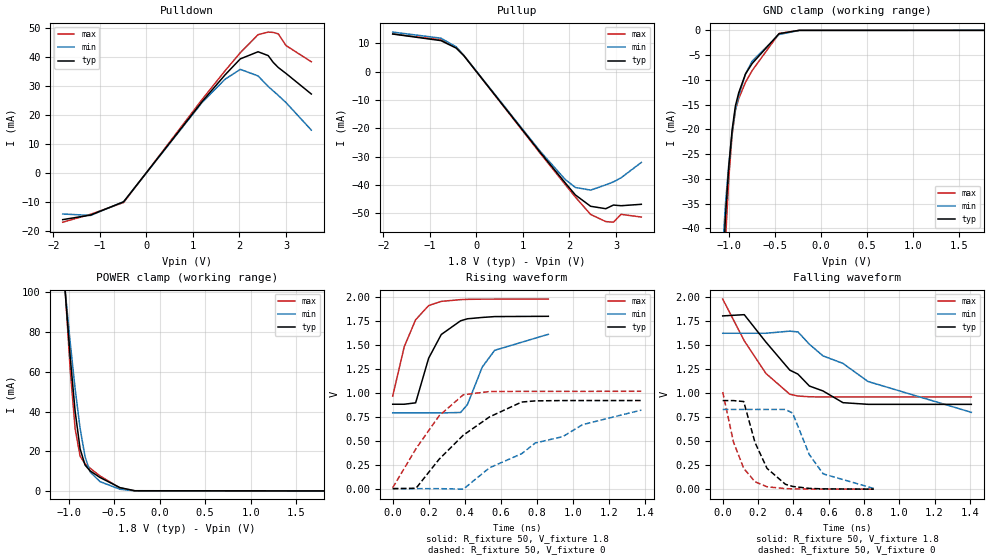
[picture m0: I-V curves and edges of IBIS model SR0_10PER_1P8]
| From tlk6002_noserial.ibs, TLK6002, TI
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[Model]   SR0_10PER_1P8
Model_type   3-state
Polarity   Non-Inverting
Enable   Active-Low
Cref =  15.0000pF
Rref =  100.0000M
Vref =  0V
Vmeas =  0.9
C_comp   1.885425p   1.715283p   2.176444p
[Temperature Range]   25   125   -40
[Voltage Range]   1.8   1.62   1.98
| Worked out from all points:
|   slope of the pulldown table from 0 to 0.27 V, typ, clamps not added: 47.1 ohm
|   slope of the pullup table from 0 to 0.27 V, typ, clamps not added: 47.4 ohm
|   GND clamp passes 1 mA (typ) near -0.48 V on its own axis
|   POWER clamp passes 1 mA (typ) near -0.39 V on its own axis
|   rising waveform, R_fixture 50, V_fixture 1.8: 20-80 % time 116ps typ, 136ps min, 105ps max; typ from 0.881 V to 1.8 V
|   rising waveform, R_fixture 50, V_fixture 0: 20-80 % time 335ps typ, 539ps min, 235ps max; typ from 0 V to 0.92 V
|   falling waveform, R_fixture 50, V_fixture 1.8: 20-80 % time 303ps typ, 537ps min, 219ps max; typ from 1.8 V to 0.882 V
|   falling waveform, R_fixture 50, V_fixture 0: 20-80 % time 117ps typ, 135ps min, 99.2ps max; typ from 0.921 V to 0.001 V
[POWER_clamp]
-1.8V     644.6mA    525mA      777mA
-1.055V   111.8mA    110.1mA    115.1mA
-1.036V   100.1mA    100.9mA    100.7mA
-981.8mV  67.73mA    75.06mA    61.46mA
-927.3mV  40.06mA    51.42mA    31.32mA
-872.7mV  21.16mA    31.46mA    17.47mA
-818.2mV  13.02mA    17.22mA    13.65mA
-763.6mV  10.12mA    9.635mA    11.46mA
-654.5mV  6.765mA    4.687mA    7.551mA
-436.4mV  1.678mA    857.7uA    1.497mA
-272.7mV  101.6uA    39.42uA    61.35uA
1.8V      90.02nA    111.7nA    348.8nA
[Pulldown]
-1.8V     -16mA      -14.06mA   -16.88mA
-1.2V     -14.43mA   -14.55mA   -14.16mA
-490.9mV  -9.876mA   -9.852mA   -10.12mA
1.2V      24.63mA    24.33mA    25.37mA
1.691V    33.76mA    32.26mA    35.17mA
2.018V    39.25mA    35.65mA    41.38mA
2.4V      41.7mA     33.4mA     47.57mA
2.618V    40.38mA    29.76mA    48.46mA
2.727V    38.02mA    28.23mA    48.35mA
2.836V    36.27mA    26.68mA    47.83mA
3V        34.26mA    24.25mA    43.84mA
3.545V    27.17mA    14.78mA    38.26mA
[Pullup]
-1.8V     13.31mA    13.99mA    13.35mA
-763.6mV  10.98mA    11.84mA    11.28mA
-436.4mV  8.351mA    8.806mA    8.623mA
-272.7mV  5.714mA    5.817mA    5.773mA
1.364V    -28.29mA   -27.93mA   -28.62mA
1.909V    -39.21mA   -38.01mA   -39.8mA
2.127V    -43.46mA   -40.83mA   -44.21mA
2.455V    -47.47mA   -41.76mA   -50.35mA
2.782V    -48.32mA   -39.91mA   -52.87mA
2.945V    -47.03mA   -38.87mA   -53.08mA
3.109V    -47.27mA   -37.41mA   -50.31mA
3.545V    -46.77mA   -32.01mA   -51.27mA
[GND_clamp]
-1.8V     -566.4mA   -409.5mA   -760.6mA
-1.073V   -54mA      -46.59mA   -65.57mA
-1.036V   -37.78mA   -35.21mA   -42.82mA
-1V       -27.67mA   -27.21mA   -30.08mA
-963.6mV  -20.15mA   -20.81mA   -21.18mA
-927.3mV  -15.22mA   -16.02mA   -16.11mA
-890.9mV  -12.56mA   -13.16mA   -13.75mA
-818.2mV  -8.811mA   -8.807mA   -10.5mA
-745.5mV  -6.683mA   -6.208mA   -8.112mA
-454.5mV  -667.9uA   -843.5uA   -644.9uA
-236.4mV  -5uA       -16.82uA   -2.48uA
1.764V    74.33nA    1.736uA    140.7nA
[Ramp]
dV/dt_f  0.4683422/0.2556061n  0.4296108/0.4864909n  0.5160574/0.1742076n
dV/dt_r  0.4626691/0.2841825n  0.4174943/0.4785458n  0.5102716/0.1846147n
R_load = 50
[Rising Waveform]
R_fixture = 50
V_fixture = 1.8
V_fixture_min = 1.62
V_fixture_max = 1.98
0s        881.4mV    790.8mV    966.8mV
64ps      881.5mV    790.8mV    1.483V
127ps     896.1mV    790.8mV    1.764V
199ps     1.362V     790.8mV    1.912V
269ps     1.61V      790.8mV    1.956V
376ps     1.753V     795.4mV    1.974V
414ps     1.774V     878.7mV    1.977V
496ps     1.788V     1.27V      1.979V
565ps     1.797V     1.445V     1.979V
862ps     1.8V       1.612V     1.98V
[Rising Waveform]
R_fixture = 50
V_fixture = 0
V_fixture_min = 0
V_fixture_max = 0
0s        2.289uV    1.08uV     9.049mV
129ps     3.596mV    971.8nV    417.7mV
257ps     306.8mV    -29.71uV   760.6mV
391ps     558.4mV    -5.602mV   980.4mV
536ps     749mV      217.7mV    1.014V
714ps     904.2mV    364.6mV    1.016V
790ps     916.6mV    477.1mV    1.016V
942ps     919.8mV    543.1mV    1.016V
1.051ns   919.9mV    667.8mV    1.016V
1.377ns   920.2mV    820.6mV    1.017V
[Falling Waveform]
R_fixture = 50
V_fixture = 1.8
V_fixture_min = 1.62
V_fixture_max = 1.98
0s        1.8V       1.62V      1.975V
122ps     1.813V     1.62V      1.542V
244ps     1.53V      1.62V      1.204V
380ps     1.237V     1.642V     986.7mV
426ps     1.196V     1.634V     968.4mV
491ps     1.072V     1.506V     960.4mV
568ps     1.021V     1.385V     958.9mV
681ps     899.3mV    1.307V     958.8mV
823ps     882.1mV    1.119V     958.7mV
1.408ns   881.7mV    799.1mV    958.5mV
[Falling Waveform]
R_fixture = 50
V_fixture = 0
V_fixture_min = 0
V_fixture_max = 0
0s        920.9mV    828.9mV    1.009V
61ps      920.8mV    828.9mV    490.5mV
119ps     911mV      828.9mV    217.3mV
183ps     484.9mV    828.9mV    78.07mV
251ps     217.2mV    829mV      26.07mV
355ps     52.24mV    828.9mV    6.935mV
396ps     29.63mV    791.1mV    4.463mV
490ps     9.417mV    361.9mV    2.735mV
569ps     4.315mV    160.1mV    2.242mV
856ps     1.465mV    8.164mV    1.264mV
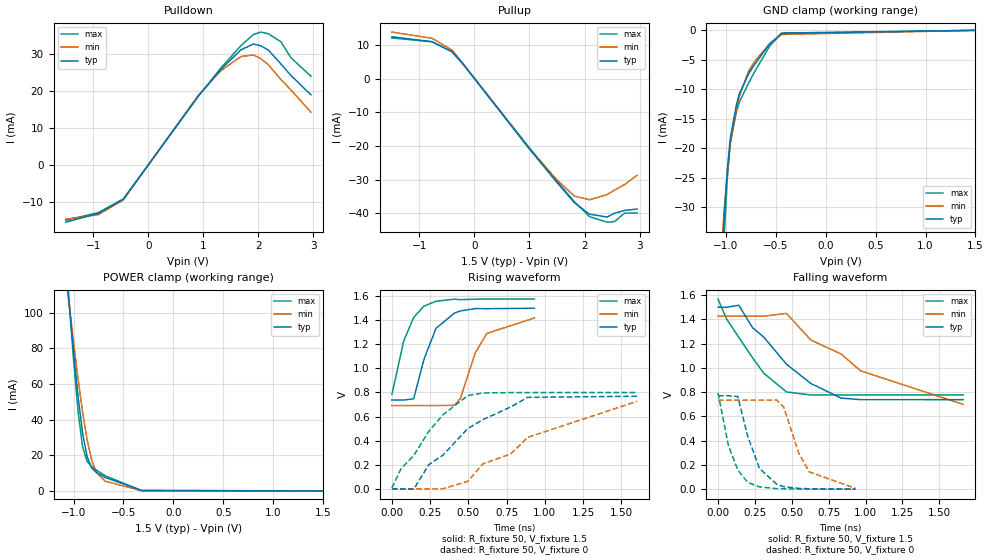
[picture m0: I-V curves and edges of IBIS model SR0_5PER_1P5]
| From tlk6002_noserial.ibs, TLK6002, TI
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[Model]   SR0_5PER_1P5
Model_type   3-state
Polarity   Non-Inverting
Enable   Active-Low
Cref =  15.0000pF
Rref =  100.0000M
Vref =  0V
Vmeas =  0.75
C_comp   2.108887p   1.924381p   2.428843p
[Temperature Range]   25   125   -40
[Voltage Range]   1.5   1.425   1.575
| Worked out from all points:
|   slope of the pulldown table from 0 to 0.225 V, typ, clamps not added: 47.1 ohm
|   slope of the pullup table from 0 to 0.225 V, typ, clamps not added: 47 ohm
|   GND clamp passes 1 mA (typ) near -0.48 V on its own axis
|   POWER clamp passes 1 mA (typ) near -0.39 V on its own axis
|   rising waveform, R_fixture 50, V_fixture 1.5: 20-80 % time 118ps typ, 137ps min, 109ps max; typ from 0.737 V to 1.5 V
|   rising waveform, R_fixture 50, V_fixture 0: 20-80 % time 414ps typ, 649ps min, 300ps max; typ from 0 V to 0.769 V
|   falling waveform, R_fixture 50, V_fixture 1.5: 20-80 % time 381ps typ, 659ps min, 274ps max; typ from 1.5 V to 0.738 V
|   falling waveform, R_fixture 50, V_fixture 0: 20-80 % time 119ps typ, 142ps min, 106ps max; typ from 0.769 V to 0.001 V
[POWER_clamp]
-1.5V     423.5mA    352.2mA    503mA
-1.061V   115.6mA    113mA      119.7mA
-1.045V   105.8mA    105.4mA    107.7mA
-1V       78.14mA    83.49mA    73.84mA
-954.5mV  53.09mA    62.89mA    44.72mA
-909.1mV  32.54mA    44.27mA    24.77mA
-863.6mV  19.13mA    28.63mA    16.48mA
-818.2mV  13.01mA    17.22mA    13.64mA
-772.7mV  10.47mA    10.51mA    11.79mA
-681.8mV  7.535mA    5.432mA    8.487mA
-318.2mV  297uA      112.4uA    206uA
1.5V      31.47nA    90.8nA     96.21nA
[Pulldown]
-1.5V     -15.59mA   -14.78mA   -15.08mA
-909.1mV  -13.19mA   -13.53mA   -12.99mA
-454.5mV  -9.369mA   -9.558mA   -9.315mA
909.1mV   18.53mA    18.79mA    18.54mA
1.318V    25.82mA    25.45mA    26.17mA
1.682V    31.06mA    29.27mA    32.21mA
1.909V    32.66mA    29.7mA     35.22mA
2.045V    32.18mA    28.69mA    35.89mA
2.182V    31mA       27.03mA    35.43mA
2.409V    27.27mA    23.05mA    33.28mA
2.591V    24.15mA    20.24mA    28.95mA
2.955V    18.91mA    14.22mA    23.95mA
[Pullup]
-1.5V     12.5mA     13.89mA    12.14mA
-772.7mV  11.03mA    12.06mA    11.02mA
-409.1mV  8.07mA     8.579mA    8.074mA
-227.3mV  4.842mA    4.968mA    4.737mA
1V        -20.87mA   -20.81mA   -20.52mA
1.5V      -30.8mA    -30.02mA   -30.43mA
1.818V    -36.84mA   -34.86mA   -36.55mA
2.091V    -40.22mA   -35.94mA   -40.93mA
2.409V    -41.07mA   -34.42mA   -42.6mA
2.545V    -39.94mA   -33.05mA   -42.43mA
2.727V    -39.1mA    -31.44mA   -39.92mA
2.955V    -38.69mA   -28.67mA   -39.87mA
[GND_clamp]
-1.5V     -337mA     -245.7mA   -453.6mA
-1.045V   -41.26mA   -37.73mA   -47.59mA
-1.015V   -31.48mA   -30.32mA   -34.73mA
-984.8mV  -23.81mA   -24.11mA   -25.24mA
-954.5mV  -18.25mA   -19.11mA   -19.1mA
-893.9mV  -12.68mA   -13.3mA    -13.81mA
-863.6mV  -10.74mA   -11.17mA   -12.17mA
-772.7mV  -7.41mA    -7.008mA   -8.983mA
-712.1mV  -5.806mA   -5.3mA     -7.048mA
-560.6mV  -2.304mA   -2.277mA   -2.676mA
-439.4mV  -510.4uA   -690.6uA   -461.1uA
1.5V      31.47nA    237.4nA    67.8nA
[Ramp]
dV/dt_f  0.3925608/0.3342369n  0.3824552/0.6069363n  0.4071581/0.2295208n
dV/dt_r  0.3873629/0.3628744n  0.3703073/0.5899429n  0.4022603/0.2467725n
R_load = 50
[Rising Waveform]
R_fixture = 50
V_fixture = 1.5
V_fixture_min = 1.425
V_fixture_max = 1.575
0s        737.4mV    691.4mV    783.3mV
77ps      737.4mV    691.4mV    1.227V
142ps     747.5mV    691.4mV    1.422V
210ps     1.077V     691.4mV    1.517V
288ps     1.332V     691.4mV    1.557V
408ps     1.458V     693.6mV    1.574V
447ps     1.476V     749.2mV    1.57V
545ps     1.496V     1.13V      1.574V
621ps     1.495V     1.29V      1.575V
931ps     1.499V     1.418V     1.575V
[Rising Waveform]
R_fixture = 50
V_fixture = 0
V_fixture_min = 0
V_fixture_max = 0
0s        874nV      1.094uV    7.831mV
60ps      376.7uV    1.085uV    168.4mV
143ps     -2.279mV   1.072uV    277.8mV
241ps     200.6mV    -6.664uV   477.8mV
334ps     280.6mV    781.7uV    615.3mV
496ps     501.3mV    63.16mV    774.3mV
595ps     574.5mV    208.4mV    796.4mV
777ps     680.3mV    289.9mV    799mV
887ps     759.5mV    427.4mV    799.2mV
1.602ns   769mV      726.5mV    799.7mV
[Falling Waveform]
R_fixture = 50
V_fixture = 1.5
V_fixture_min = 1.425
V_fixture_max = 1.575
0s        1.5V       1.425V     1.566V
56ps      1.498V     1.425V     1.406V
141ps     1.515V     1.425V     1.25V
235ps     1.329V     1.425V     1.081V
310ps     1.253V     1.425V     955.6mV
464ps     1.03V      1.448V     801.1mV
629ps     871.1mV    1.229V     776.8mV
834ps     750.6mV    1.114V     776.6mV
966ps     738mV      975.5mV    776.6mV
1.662ns   737.6mV    698.6mV    776.5mV
[Falling Waveform]
R_fixture = 50
V_fixture = 0
V_fixture_min = 0
V_fixture_max = 0
0s        769.5mV    733.7mV    793.5mV
70ps      769.4mV    733.7mV    362.5mV
134ps     764.4mV    733.7mV    158.4mV
201ps     438.4mV    733.7mV    57.05mV
281ps     171.8mV    733.9mV    19.54mV
399ps     40.35mV    734.5mV    5.008mV
445ps     21.59mV    678mV      4.25mV
547ps     7.941mV    298.5mV    2.003mV
619ps     4.096mV    142.9mV    1.638mV
932ps     1.18mV     7.197mV    960.1uV
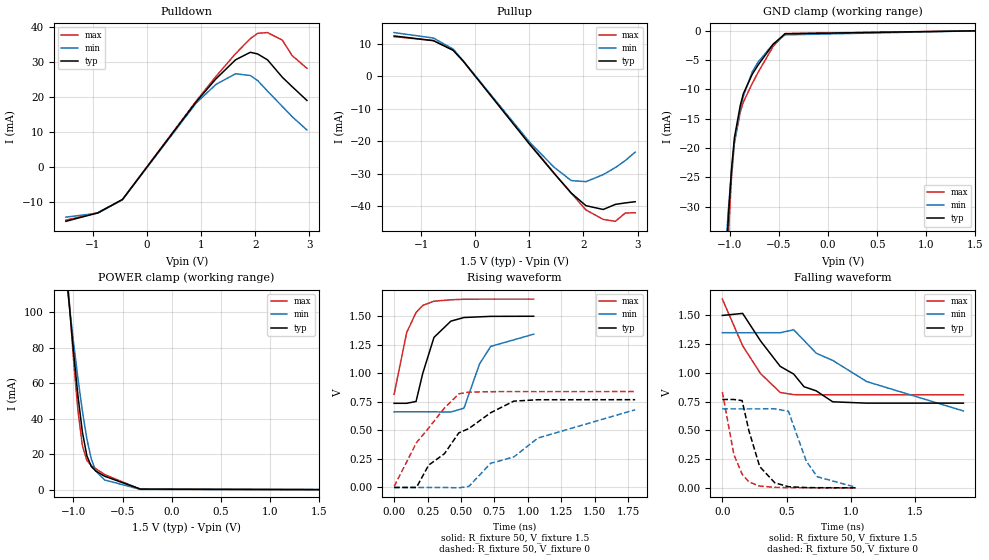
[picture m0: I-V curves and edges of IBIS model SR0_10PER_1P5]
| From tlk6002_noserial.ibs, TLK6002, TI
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[Model]   SR0_10PER_1P5
Model_type   3-state
Polarity   Non-Inverting
Enable   Active-Low
Cref =  15.0000pF
Rref =  100.0000M
Vref =  0V
Vmeas =  0.75
C_comp   2.108887p   1.924381p   2.428843p
[Temperature Range]   25   125   -40
[Voltage Range]   1.5   1.35   1.65
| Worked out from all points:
|   slope of the pulldown table from 0 to 0.225 V, typ, clamps not added: 47.1 ohm
|   slope of the pullup table from 0 to 0.225 V, typ, clamps not added: 47 ohm
|   GND clamp passes 1 mA (typ) near -0.48 V on its own axis
|   POWER clamp passes 1 mA (typ) near -0.39 V on its own axis
|   rising waveform, R_fixture 50, V_fixture 1.5: 20-80 % time 118ps typ, 140ps min, 109ps max; typ from 0.737 V to 1.5 V
|   rising waveform, R_fixture 50, V_fixture 0: 20-80 % time 414ps typ, 717ps min, 284ps max; typ from 0 V to 0.769 V
|   falling waveform, R_fixture 50, V_fixture 1.5: 20-80 % time 382ps typ, 732ps min, 260ps max; typ from 1.5 V to 0.738 V
|   falling waveform, R_fixture 50, V_fixture 0: 20-80 % time 120ps typ, 146ps min, 105ps max; typ from 0.769 V to 0.001 V
[POWER_clamp]
-1.5V     423.5mA    352.2mA    503mA
-1.061V   115.6mA    113mA      119.8mA
-1.045V   105.8mA    105.4mA    107.7mA
-1V       78.14mA    83.49mA    73.84mA
-954.5mV  53.09mA    62.89mA    44.72mA
-909.1mV  32.54mA    44.27mA    24.77mA
-863.6mV  19.13mA    28.63mA    16.48mA
-818.2mV  13.01mA    17.22mA    13.64mA
-772.7mV  10.47mA    10.51mA    11.79mA
-681.8mV  7.535mA    5.431mA    8.488mA
-318.2mV  297uA      112.4uA    206.1uA
1.5V      31.47nA    84.52nA    126.1nA
[Pulldown]
-1.5V     -15.59mA   -14.4mA    -15.27mA
-909.1mV  -13.19mA   -13.27mA   -13.12mA
-454.5mV  -9.369mA   -9.419mA   -9.379mA
909.1mV   18.53mA    18.18mA    18.76mA
1.273V    25.07mA    23.48mA    25.76mA
1.636V    30.51mA    26.53mA    32.26mA
1.909V    32.66mA    26.03mA    36.57mA
2.045V    32.18mA    24.59mA    38.07mA
2.227V    30.5mA     21.57mA    38.29mA
2.5V      25.54mA    17.21mA    36.13mA
2.682V    22.85mA    14.28mA    31.72mA
2.955V    18.91mA    10.48mA    28.08mA
[Pullup]
-1.5V     12.5mA     13.54mA    12.26mA
-772.7mV  11.03mA    11.84mA    11.09mA
-409.1mV  8.07mA     8.448mA    8.113mA
-227.3mV  4.842mA    4.891mA    4.759mA
1V        -20.87mA   -20.22mA   -20.66mA
1.455V    -29.92mA   -28.02mA   -29.78mA
1.773V    -36mA      -32.16mA   -36.04mA
2.045V    -39.91mA   -32.5mA    -41.22mA
2.364V    -41.09mA   -30.34mA   -44.15mA
2.591V    -39.51mA   -28.12mA   -44.74mA
2.773V    -39.06mA   -25.98mA   -42.17mA
2.955V    -38.69mA   -23.37mA   -42.1mA
[GND_clamp]
-1.5V     -337mA     -245.7mA   -453.6mA
-1.045V   -41.26mA   -37.73mA   -47.59mA
-1.015V   -31.48mA   -30.32mA   -34.73mA
-984.8mV  -23.81mA   -24.11mA   -25.24mA
-954.5mV  -18.25mA   -19.11mA   -19.1mA
-893.9mV  -12.68mA   -13.3mA    -13.81mA
-863.6mV  -10.74mA   -11.17mA   -12.17mA
-772.7mV  -7.41mA    -7.007mA   -8.984mA
-712.1mV  -5.806mA   -5.299mA   -7.049mA
-560.6mV  -2.304mA   -2.277mA   -2.676mA
-439.4mV  -510.4uA   -690.3uA   -461.4uA
1.5V      31.47nA    1.543uA    64.91nA
[Ramp]
dV/dt_f  0.3923686/0.3345253n   0.358796/0.6770248n  0.4274046/0.2152316n
dV/dt_r  0.3874096/0.3632445n   0.347389/0.6532747n  0.4223533/0.2307123n
R_load = 50
[Rising Waveform]
R_fixture = 50
V_fixture = 1.5
V_fixture_min = 1.35
V_fixture_max = 1.65
0s        737.4mV    662.6mV    816.1mV
94ps      737.4mV    662.6mV    1.358V
164ps     753.5mV    662.6mV    1.533V
214ps     999.7mV    662.6mV    1.595V
298ps     1.315V     662.6mV    1.632V
424ps     1.457V     661.4mV    1.644V
522ps     1.489V     694.6mV    1.649V
639ps     1.495V     1.084V     1.65V
722ps     1.499V     1.236V     1.65V
1.043ns   1.5V       1.343V     1.65V
[Rising Waveform]
R_fixture = 50
V_fixture = 0
V_fixture_min = 0
V_fixture_max = 0
0s        887.4nV    537nV      8.348mV
167ps     375.3uV    323.4nV    392.7mV
258ps     195.7mV    207nV      520.4mV
376ps     295.7mV    123.1uV    696.3mV
483ps     477.9mV    -3.364mV   819.9mV
559ps     516.6mV    9.666mV    835.8mV
721ps     654.5mV    211.6mV    839.3mV
894ps     756.4mV    267.3mV    839.6mV
1.075ns   768.6mV    433.3mV    839.8mV
1.801ns   769.1mV    680.9mV    840.3mV
[Falling Waveform]
R_fixture = 50
V_fixture = 1.5
V_fixture_min = 1.35
V_fixture_max = 1.65
0s        1.5V       1.35V      1.642V
158ps     1.518V     1.35V      1.237V
298ps     1.278V     1.35V      994.1mV
451ps     1.057V     1.35V      830.4mV
556ps     990.3mV    1.375V     811.4mV
636ps     880.4mV    1.283V     809.9mV
731ps     844.7mV    1.172V     809.9mV
860ps     749.1mV    1.109V     809.9mV
1.125ns   737.5mV    925.1mV    809.8mV
1.878ns   737.6mV    669.5mV    809.7mV
[Falling Waveform]
R_fixture = 50
V_fixture = 0
V_fixture_min = 0
V_fixture_max = 0
0s        769.5mV    687.7mV    834.6mV
90ps      769.2mV    687.7mV    290mV
154ps     759.8mV    687.7mV    119.5mV
207ps     497.5mV    687.7mV    52.4mV
291ps     185.9mV    687.7mV    16.07mV
409ps     44.46mV    687.9mV    5.547mV
515ps     10.94mV    666.5mV    2.287mV
654ps     3.4mV      232.6mV    1.596mV
740ps     2.317mV    97.03mV    1.369mV
1.038ns   995.3uV    6.854mV    801.2uV
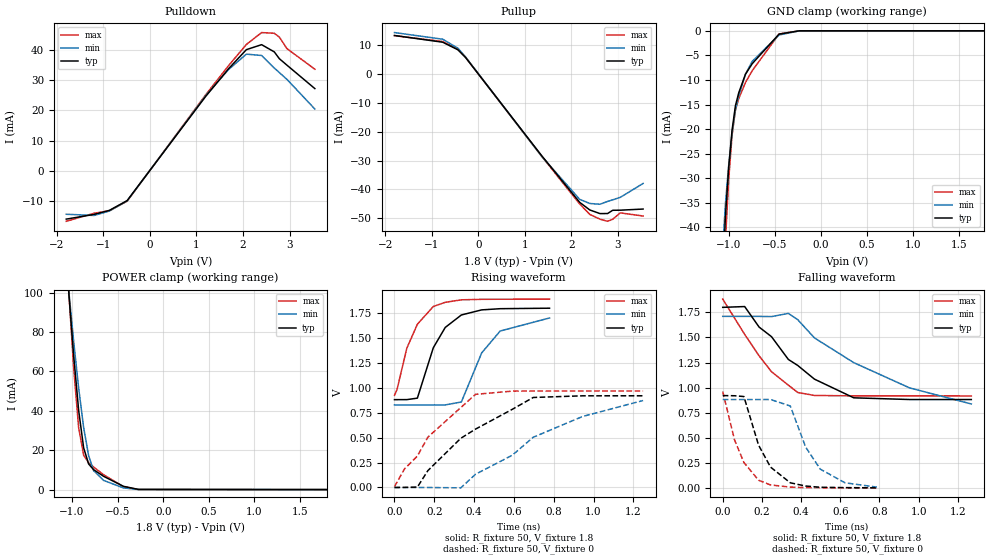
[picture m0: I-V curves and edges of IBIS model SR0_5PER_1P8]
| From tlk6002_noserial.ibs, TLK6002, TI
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[Model]   SR0_5PER_1P8
Model_type   3-state
Polarity   Non-Inverting
Enable   Active-Low
Cref =  15.0000pF
Rref =  100.0000M
Vref =  0V
Vmeas =  0.9
C_comp   1.885425p   1.715283p   2.176444p
[Temperature Range]   25   125   -40
[Voltage Range]   1.8   1.71   1.89
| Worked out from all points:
|   slope of the pulldown table from 0 to 0.27 V, typ, clamps not added: 47.1 ohm
|   slope of the pullup table from 0 to 0.27 V, typ, clamps not added: 47.4 ohm
|   GND clamp passes 1 mA (typ) near -0.48 V on its own axis
|   POWER clamp passes 1 mA (typ) near -0.39 V on its own axis
|   rising waveform, R_fixture 50, V_fixture 1.8: 20-80 % time 116ps typ, 135ps min, 106ps max; typ from 0.881 V to 1.8 V
|   rising waveform, R_fixture 50, V_fixture 0: 20-80 % time 334ps typ, 499ps min, 245ps max; typ from 0 V to 0.92 V
|   falling waveform, R_fixture 50, V_fixture 1.8: 20-80 % time 303ps typ, 492ps min, 227ps max; typ from 1.8 V to 0.882 V
|   falling waveform, R_fixture 50, V_fixture 0: 20-80 % time 117ps typ, 133ps min, 101ps max; typ from 0.921 V to 0.002 V
[POWER_clamp]
-1.8V     644.6mA    525mA      776.9mA
-1.055V   111.8mA    110.1mA    115.1mA
-1.036V   100.1mA    100.9mA    100.7mA
-981.8mV  67.73mA    75.06mA    61.45mA
-927.3mV  40.06mA    51.42mA    31.31mA
-872.7mV  21.16mA    31.46mA    17.46mA
-818.2mV  13.02mA    17.22mA    13.64mA
-763.6mV  10.12mA    9.635mA    11.46mA
-654.5mV  6.765mA    4.687mA    7.549mA
-436.4mV  1.678mA    857.7uA    1.497mA
-272.7mV  101.6uA    39.45uA    61.06uA
1.8V      90.02nA    124.6nA    271nA
[Pulldown]
-1.8V     -16mA      -14.39mA   -16.72mA
-1.2V     -14.43mA   -14.79mA   -14.05mA
-872.7mV  -13.11mA   -13.32mA   -13.24mA
-490.9mV  -9.876mA   -9.958mA   -10.07mA
1.2V      24.63mA    24.88mA    25.17mA
1.691V    33.76mA    33.5mA     34.78mA
2.073V    40.05mA    38.56mA    41.76mA
2.4V      41.7mA     38.12mA    45.7mA
2.673V    39.31mA    33.97mA    45.46mA
2.782V    37.05mA    32.46mA    44.2mA
2.945V    34.92mA    30.22mA    40.39mA
3.545V    27.17mA    20.41mA    33.58mA
[Pullup]
-1.8V     13.31mA    14.32mA    13.24mA
-763.6mV  10.98mA    12.02mA    11.23mA
-436.4mV  8.351mA    8.912mA    8.593mA
-272.7mV  5.714mA    5.884mA    5.754mA
1.364V    -28.29mA   -28.5mA    -28.48mA
2.182V    -44.46mA   -43.42mA   -45.01mA
2.4V      -47.09mA   -44.84mA   -48.63mA
2.618V    -48.34mA   -45.11mA   -50.27mA
2.782V    -48.32mA   -44.12mA   -51.01mA
2.891V    -47.2mA    -43.59mA   -50.31mA
3.055V    -47.16mA   -42.72mA   -48.1mA
3.545V    -46.77mA   -37.91mA   -49.18mA
[GND_clamp]
-1.8V     -566.4mA   -409.5mA   -760.6mA
-1.073V   -54mA      -46.59mA   -65.56mA
-1.036V   -37.78mA   -35.22mA   -42.81mA
-1V       -27.67mA   -27.21mA   -30.08mA
-963.6mV  -20.15mA   -20.81mA   -21.17mA
-927.3mV  -15.22mA   -16.02mA   -16.11mA
-890.9mV  -12.56mA   -13.16mA   -13.75mA
-818.2mV  -8.811mA   -8.808mA   -10.5mA
-745.5mV  -6.683mA   -6.209mA   -8.111mA
-454.5mV  -667.9uA   -843.8uA   -644.4uA
-236.4mV  -5uA       -16.85uA   -2.331uA
1.764V    74.33nA    230.2nA    154.6nA
[Ramp]
dV/dt_f  0.4684859/0.2555015n  0.4556346/0.4433514n  0.4919892/0.1828553n
dV/dt_r  0.4626933/0.2839431n  0.4434752/0.4400823n  0.4863194/0.1943181n
R_load = 50
[Rising Waveform]
R_fixture = 50
V_fixture = 1.8
V_fixture_min = 1.71
V_fixture_max = 1.89
0s        881.4mV    828.6mV    924.4mV
13ps      881.4mV    828.6mV    984.7mV
62ps      881.6mV    828.6mV    1.398V
115ps     896.5mV    828.6mV    1.638V
195ps     1.402V     828.6mV    1.816V
255ps     1.606V     828.5mV    1.858V
336ps     1.731V     857.9mV    1.883V
438ps     1.782V     1.35V      1.888V
531ps     1.794V     1.57V      1.889V
779ps     1.799V     1.701V     1.89V
[Rising Waveform]
R_fixture = 50
V_fixture = 0
V_fixture_min = 0
V_fixture_max = 0
0s        2.222uV    1.227uV    8.596mV
50ps      669.7uV    1.192uV    185.2mV
115ps     3.909mV    1.147uV    315.9mV
168ps     169.7mV    1.051uV    505.6mV
333ps     493.5mV    -3.798mV   801.6mV
407ps     585.4mV    132.6mV    934.6mV
592ps     784.5mV    323.9mV    967.1mV
697ps     903.2mV    503.9mV    967.5mV
945ps     919.8mV    712.5mV    968.1mV
1.249ns   920.1mV    872.7mV    968.5mV
[Falling Waveform]
R_fixture = 50
V_fixture = 1.8
V_fixture_min = 1.71
V_fixture_max = 1.89
0s        1.8V       1.71V      1.882V
112ps     1.808V     1.71V      1.531V
186ps     1.603V     1.71V      1.316V
249ps     1.508V     1.708V     1.159V
335ps     1.281V     1.74V      1.025V
383ps     1.221V     1.677V     951.7mV
468ps     1.085V     1.496V     922.2mV
669ps     898.6mV    1.249V     917.9mV
954ps     881.6mV    997.4mV    917.8mV
1.269ns   881.7mV    837.4mV    917.6mV
[Falling Waveform]
R_fixture = 50
V_fixture = 0
V_fixture_min = 0
V_fixture_max = 0
0s        920.9mV    881.3mV    962.1mV
60ps      919.3mV    881.3mV    480.1mV
108ps     911.4mV    881.3mV    254.9mV
183ps     426.9mV    881.3mV    77.33mV
244ps     208.3mV    881.9mV    30.41mV
345ps     51.72mV    817.2mV    8.859mV
423ps     19.65mV    409.1mV    3.69mV
498ps     7.394mV    187.9mV    2.581mV
624ps     3.802mV    52mV       1.915mV
787ps     1.628mV    8.616mV    1.423mV
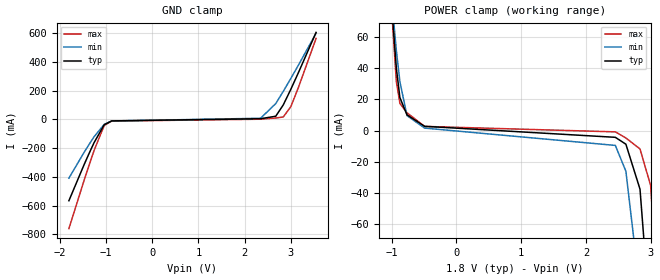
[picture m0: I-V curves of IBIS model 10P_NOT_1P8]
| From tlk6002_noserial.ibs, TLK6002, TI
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[Model]   10P_NOT_1P8
Model_type   Input
Polarity   Non-Inverting
Vinh =  1
Vinl =  0.8
C_comp   1.885425p   1.715283p   2.176444p
[Model Spec]
Vinh   1   0.91   1.09
Vinl   0.8   0.71   0.89
[Temperature Range]   25   125   -40
[Voltage Range]   1.8   1.62   1.98
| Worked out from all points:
|   GND clamp passes 1 mA (typ) near -0.48 V on its own axis
|   POWER clamp passes 1 mA (typ) near -0.39 V on its own axis
[POWER_clamp]
-1.8V     644.6mA    525mA      777mA
-1.036V   100.1mA    100.9mA    100.7mA
-927.3mV  40.06mA    51.42mA    31.32mA
-872.7mV  21.16mA    31.46mA    17.47mA
-763.6mV  10.12mA    9.635mA    11.46mA
-490.9mV  2.713mA    1.554mA    2.653mA
2.455V    -4.375mA   -9.587mA   -865uA
2.618V    -8.811mA   -26.24mA   -4.795mA
2.836V    -37.78mA   -103.8mA   -11.88mA
3V        -126.4mA   -183.4mA   -35.36mA
3.109V    -199.8mA   -239.9mA   -106.4mA
3.545V    -523.2mA   -483.6mA   -518.8mA
[GND_clamp]
-1.8V     -566.4mA   -409.5mA   -760.6mA
-1.473V   -317mA     -231.3mA   -426.6mA
-1.364V   -238.1mA   -175.1mA   -320.1mA
-1.255V   -162.4mA   -121.6mA   -216.8mA
-1.036V   -37.78mA   -35.21mA   -42.82mA
-872.7mV  -11.23mA   -11.73mA   -12.57mA
2.345V    3.933mA    7.09mA     532.8uA
2.673V    21.16mA    109mA      8.877mA
2.836V    100.1mA    194.4mA    15.86mA
3V        209mA      284.5mA    88.34mA
3.164V    324.8mA    377mA      222mA
3.545V    604.1mA    598.2mA    562.5mA
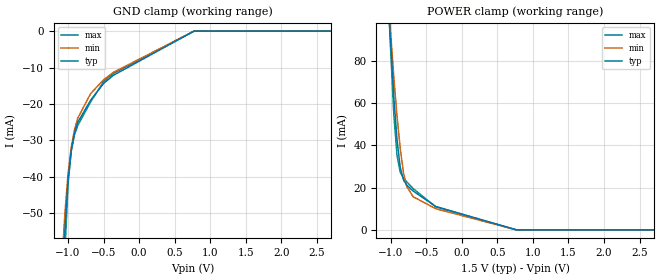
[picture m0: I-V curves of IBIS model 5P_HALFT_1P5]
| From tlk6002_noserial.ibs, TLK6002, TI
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[Model]   5P_HALFT_1P5
Model_type   Input
Polarity   Non-Inverting
Vinh =  0.85
Vinl =  0.65
C_comp   2.108887p   1.924381p   2.428843p
[Model Spec]
Vinh   0.85   0.8125   0.8875
Vinl   0.65   0.6125   0.6875
[Temperature Range]   25   125   -40
[Voltage Range]   1.5   1.425   1.575
[POWER_clamp]
-1.5V     431.5mA    359.6mA    511.4mA
-1.091V   144.4mA    137.2mA    153.4mA
-1.045V   115.3mA    114.5mA    117.3mA
-954.5mV  62.89mA    72.23mA    54.76mA
-909.1mV  42.57mA    53.76mA    35.17mA
-863.6mV  29.45mA    38.3mA     27.19mA
-818.2mV  23.55mA    27.08mA    24.47mA
-772.7mV  21.14mA    20.54mA    22.7mA
-681.8mV  18.34mA    15.65mA    19.49mA
-363.6mV  11.06mA    9.979mA    10.87mA
772.7mV   0A         0A         -33.53uA
3V        0A         0A         -33.53uA
[GND_clamp]
-1.5V     -351.3mA   -257.1mA   -467.1mA
-1.091V   -76.16mA   -64.69mA   -90.16mA
-1.045V   -55.4mA    -50.22mA   -60.97mA
-1V       -40.88mA   -39.19mA   -41.96mA
-954.5mV  -32.61mA   -31.77mA   -32.89mA
-909.1mV  -28.01mA   -27.06mA   -28.42mA
-863.6mV  -25.03mA   -23.87mA   -25.9mA
-681.8mV  -18.92mA   -17.12mA   -19.39mA
-500mV    -14.34mA   -13.36mA   -13.89mA
-363.6mV  -12.14mA   -11.33mA   -11.61mA
772.7mV   0A         0A         0A
3V        0A         0A         0A
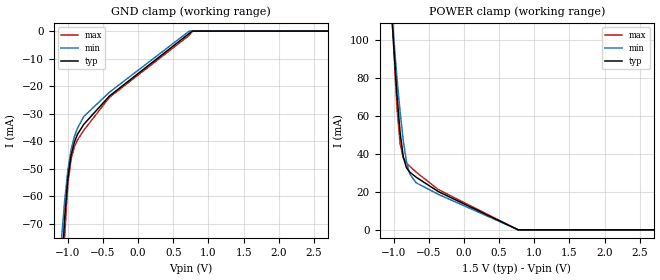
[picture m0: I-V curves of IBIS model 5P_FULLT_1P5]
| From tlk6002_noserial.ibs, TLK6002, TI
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[Model]   5P_FULLT_1P5
Model_type   Input
Polarity   Non-Inverting
Vinh =  0.85
Vinl =  0.65
C_comp   2.108887p   1.924381p   2.428843p
[Model Spec]
Vinh   0.85   0.8125   0.8875
Vinl   0.65   0.6125   0.6875
[Temperature Range]   25   125   -40
[Voltage Range]   1.5   1.425   1.575
[POWER_clamp]
-1.5V     438.6mA    366.3mA    519.8mA
-1.091V   152.5mA    145.2mA    162.9mA
-1.045V   123.5mA    122.6mA    126.9mA
-954.5mV  71.46mA    80.64mA    64.81mA
-909.1mV  51.36mA    62.31mA    45.59mA
-863.6mV  38.48mA    47.01mA    37.9mA
-818.2mV  32.78mA    35.96mA    35.31mA
-772.7mV  30.47mA    29.57mA    33.62mA
-681.8mV  27.79mA    24.85mA    30.49mA
-363.6mV  20.14mA    18.7mA     21.22mA
772.7mV   0A         0A         -67.01uA
3V        0A         0A         -67.01uA
[GND_clamp]
-1.5V     -363.8mA   -267.4mA   -480.7mA
-1.091V   -88.46mA   -75.86mA   -103.4mA
-1.045V   -67.78mA   -61.46mA   -74.37mA
-1V       -53.37mA   -50.51mA   -55.63mA
-954.5mV  -45.18mA   -43.16mA   -46.69mA
-909.1mV  -40.56mA   -38.48mA   -42.21mA
-863.6mV  -37.54mA   -35.3mA    -39.62mA
-772.7mV  -33.89mA   -31.04mA   -36.04mA
-409.1mV  -23.62mA   -22.24mA   -24.09mA
727.3mV   -844.6uA   0A         -1.539mA
772.7mV   0A         0A         0A
3V        0A         0A         0A
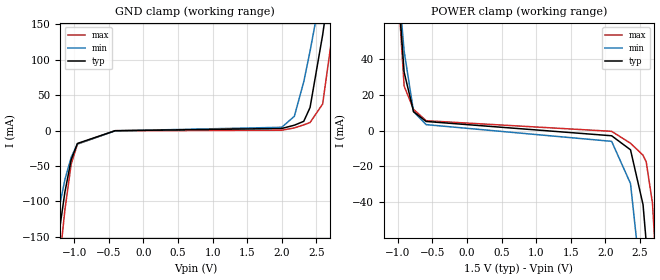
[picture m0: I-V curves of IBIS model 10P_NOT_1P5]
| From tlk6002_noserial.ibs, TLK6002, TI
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[Model]   10P_NOT_1P5
Model_type   Input
Polarity   Non-Inverting
Vinh =  0.85
Vinl =  0.65
C_comp   2.108887p   1.924381p   2.428843p
[Model Spec]
Vinh   0.85   0.775   0.925
Vinl   0.65   0.575   0.725
[Temperature Range]   25   125   -40
[Voltage Range]   1.5   1.35   1.65
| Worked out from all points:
|   GND clamp passes 1 mA (typ) near -0.48 V on its own axis
|   POWER clamp passes 1 mA (typ) near -0.39 V on its own axis
[POWER_clamp]
-1.5V     423.5mA    352.2mA    503mA
-1.045V   105.8mA    105.4mA    107.7mA
-909.1mV  32.54mA    44.27mA    24.77mA
-772.7mV  10.47mA    10.51mA    11.79mA
-590.9mV  5.058mA    3.284mA    5.459mA
2.091V    -2.919mA   -6.025mA   -440.5uA
2.364V    -10.74mA   -29.55mA   -7.091mA
2.545V    -41.26mA   -94.45mA   -13.75mA
2.591V    -62.1mA    -115.2mA   -17.46mA
2.682V    -114.8mA   -159.1mA   -40.59mA
2.773V    -174.7mA   -205.3mA   -101.3mA
2.955V    -303.7mA   -301.5mA   -263.6mA
[GND_clamp]
-1.5V     -337mA     -245.7mA   -453.6mA
-1.136V   -87.16mA   -69.43mA   -112.3mA
-1.045V   -41.26mA   -37.73mA   -47.59mA
-954.5mV  -18.25mA   -19.11mA   -19.1mA
-409.1mV  -271uA     -434.7uA   -205.5uA
2V        2.904mA    4.574mA    401.1uA
2.182V    7.535mA    20.14mA    3.711mA
2.318V    13.01mA    68.9mA     8.014mA
2.409V    32.54mA    112.2mA    11.28mA
2.591V    135.1mA    207.7mA    37.52mA
2.727V    227.9mA    283mA      132.9mA
2.955V    390.4mA    411.9mA    327.7mA
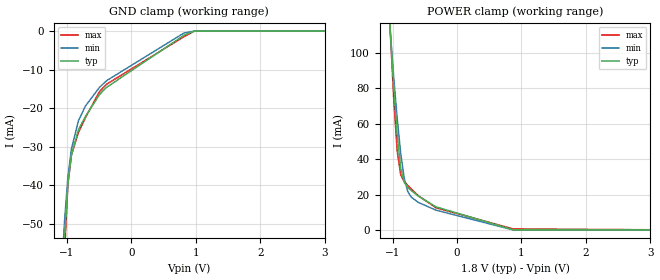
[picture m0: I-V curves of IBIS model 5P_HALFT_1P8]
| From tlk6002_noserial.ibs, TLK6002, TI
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[Model]   5P_HALFT_1P8
Model_type   Input
Polarity   Non-Inverting
Vinh =  1
Vinl =  0.8
C_comp   1.885425p   1.715283p   2.176444p
[Model Spec]
Vinh   1   0.955   1.045
Vinl   0.8   0.755   0.845
[Temperature Range]   25   125   -40
[Voltage Range]   1.8   1.71   1.89
[POWER_clamp]
-1.8V     655.3mA    533.7mA    787.8mA
-1.036V   113mA      112.2mA    113.3mA
-981.8mV  80.74mA    86.44mA    74.27mA
-927.3mV  53.3mA     62.95mA    44.51mA
-872.7mV  34.75mA    43.16mA    31.09mA
-818.2mV  26.87mA    29.13mA    27.38mA
-763.6mV  24.06mA    21.71mA    25.19mA
-709.1mV  22.28mA    18.52mA    23.16mA
-600mV    19.15mA    15.59mA    19.31mA
-327.3mV  13.08mA    11.2mA     12.55mA
872.7mV   100.3uA    0A         567uA
3.6V      0A         0A         0A
[GND_clamp]
-1.8V     -583.5mA   -422.6mA   -776.8mA
-1.091V   -78.82mA   -66.76mA   -92.32mA
-1.036V   -54.59mA   -49.73mA   -58.43mA
-981.8mV  -39.57mA   -37.78mA   -39.65mA
-927.3mV  -32.19mA   -30.6mA    -32.11mA
-818.2mV  -25.56mA   -23.24mA   -26.28mA
-709.1mV  -22.12mA   -19.4mA    -22.41mA
-490.9mV  -16.43mA   -14.57mA   -15.67mA
-381.8mV  -14.58mA   -12.85mA   -13.77mA
818.2mV   -1.106mA   -498uA     -1.451mA
981.8mV   0A         0A         0A
3.6V      0A         0A         0A
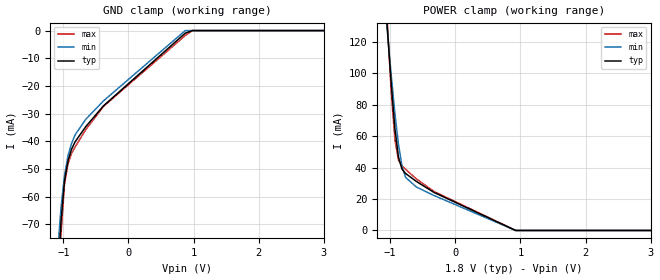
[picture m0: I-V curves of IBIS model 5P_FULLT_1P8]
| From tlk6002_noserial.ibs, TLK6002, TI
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[Model]   5P_FULLT_1P8
Model_type   Input
Polarity   Non-Inverting
Vinh =  1
Vinl =  0.8
C_comp   1.885425p   1.715283p   2.176444p
[Model Spec]
Vinh   1   0.955   1.045
Vinl   0.8   0.755   0.845
[Temperature Range]   25   125   -40
[Voltage Range]   1.8   1.71   1.89
[POWER_clamp]
-1.8V     664.6mA    542.4mA    798.8mA
-1.091V   158.9mA    150.5mA    168.9mA
-1.036V   124.2mA    123.4mA    125.9mA
-981.8mV  92.13mA    97.82mA    87.09mA
-927.3mV  64.9mA     74.48mA    57.71mA
-872.7mV  46.65mA    54.86mA    44.72mA
-818.2mV  39mA       41.03mA    41.11mA
-763.6mV  36.26mA    33.78mA    38.92mA
-600mV    31.27mA    27.7mA     32.87mA
-327.3mV  24.2mA     22.24mA    24.83mA
927.3mV   0A         0A         29.92uA
3.6V      0A         0A         0A
[GND_clamp]
-1.8V     -598.5mA   -435.7mA   -793.1mA
-1.091V   -93.44mA   -81.24mA   -107.7mA
-1.036V   -69.3mA    -64.25mA   -74.06mA
-981.8mV  -54.41mA   -52.35mA   -55.6mA
-927.3mV  -47.03mA   -45.18mA   -48.1mA
-872.7mV  -42.86mA   -40.78mA   -44.41mA
-818.2mV  -40.2mA    -37.67mA   -42.06mA
-654.5mV  -34.72mA   -32.06mA   -35.81mA
-381.8mV  -27.18mA   -25.4mA    -27.41mA
872.7mV   -941uA     0A         -1.793mA
981.8mV   0A         0A         0A
3.6V      0A         0A         0A
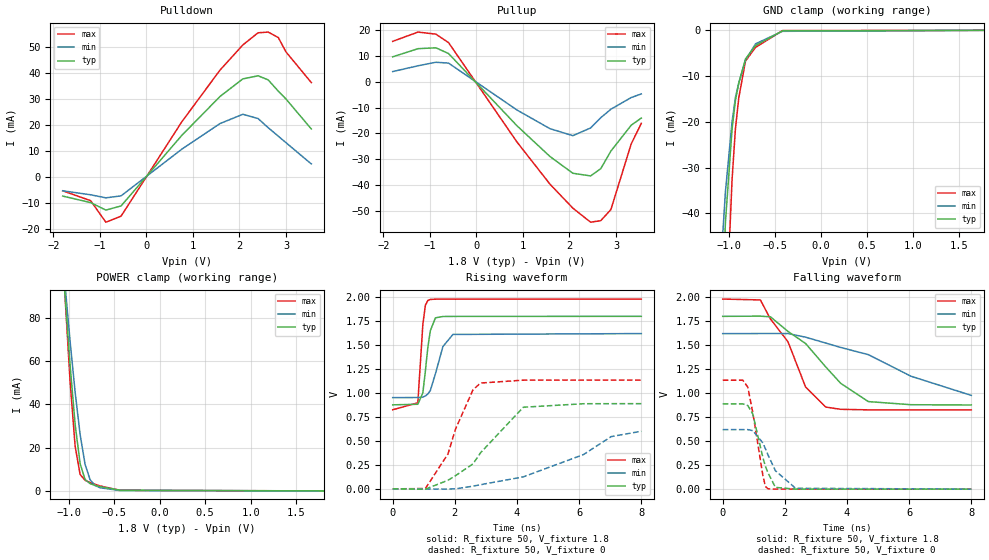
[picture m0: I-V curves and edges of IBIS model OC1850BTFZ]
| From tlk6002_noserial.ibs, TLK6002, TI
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[Model]   OC1850BTFZ
Model_type   3-state
Polarity   Non-Inverting
Enable   Active-Low
Cref =  15.0000pF
Rref =  100.0000M
Vref =  0V
Vmeas =  0.9
C_comp   1.025172p   0.8279542p   1.298979p
[Temperature Range]   25   125   -40
[Voltage Range]   1.8   1.62   1.98
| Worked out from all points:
|   slope of the pulldown table from 0 to 0.27 V, typ, clamps not added: 45.7 ohm
|   slope of the pullup table from 0 to 0.27 V, typ, clamps not added: 49.4 ohm
|   GND clamp passes 1 mA (typ) near -0.54 V on its own axis
|   POWER clamp passes 1 mA (typ) near -0.54 V on its own axis
|   rising waveform, R_fixture 50, V_fixture 1.8: 20-80 % time 204ps typ, 341ps min, 143ps max; typ from 0.877 V to 1.8 V
|   rising waveform, R_fixture 50, V_fixture 0: 20-80 % time 1.48ns typ, 2.52ns min, 970ps max; typ from 0 V to 0.889 V
|   falling waveform, R_fixture 50, V_fixture 1.8: 20-80 % time 1.77ns typ, 3.17ns min, 1.1ns max; typ from 1.8 V to 0.877 V
|   falling waveform, R_fixture 50, V_fixture 0: 20-80 % time 415ps typ, 565ps min, 333ps max; typ from 0.889 V to 0 V
[POWER_clamp]
-1.8V     626.5mA    508.8mA    755.8mA
-1.055V   100.8mA    103.1mA    102.4mA
-1.036V   89.33mA    94.12mA    88.27mA
-981.8mV  57.65mA    68.73mA    49.97mA
-927.3mV  30.72mA    45.57mA    20.64mA
-872.7mV  12.58mA    26.06mA    7.613mA
-818.2mV  5.289mA    12.28mA    4.901mA
-763.6mV  3.367mA    5.193mA    3.888mA
-709.1mV  2.574mA    2.507mA    3.06mA
-654.5mV  1.98mA     1.476mA    2.307mA
-436.4mV  343.9uA    170.5uA    303.6uA
1.8V      143.8nA    121.3nA    204.6nA
[Pulldown]
-1.8V     -7.226mA   -5.191mA   -5.197mA
-1.2V     -9.73mA    -6.722mA   -8.984mA
-872.7mV  -12.61mA   -7.901mA   -17.27mA
-545.5mV  -11.02mA   -7.145mA   -14.95mA
763.6mV   16.19mA    10.86mA    21.42mA
1.582V    31.1mA     20.68mA    41.25mA
2.073V    37.87mA    24.25mA    50.93mA
2.4V      39.06mA    22.61mA    55.6mA
2.618V    37.48mA    19.08mA    55.87mA
2.836V    33.12mA    15.81mA    53.75mA
3V        30.13mA    13.33mA    48.25mA
3.545V    18.59mA    5.139mA    36.44mA
[Pullup]
-1.8V     9.588mA    3.896mA    15.57mA
-1.255V   12.74mA    6.138mA    19.14mA
-872.7mV  13.08mA    7.495mA    18.35mA
-600mV    10.87mA    7.175mA    15.09mA
872.7mV   -17.04mA   -10.95mA   -23.32mA
1.582V    -28.9mA    -18.15mA   -39.58mA
2.073V    -35.35mA   -20.84mA   -48.82mA
2.455V    -36.38mA   -17.87mA   -54.24mA
2.673V    -33.6mA    -13.91mA   -53.65mA
2.891V    -26.78mA   -10.63mA   -49.37mA
3.327V    -16.83mA   -6.129mA   -24.05mA
3.545V    -14.04mA   -4.728mA   -16.08mA
[GND_clamp]
-1.8V     -597.6mA   -415.2mA   -913.8mA
-1.145V   -101.4mA   -74.85mA   -162.5mA
-1.109V   -79.51mA   -60.41mA   -127.5mA
-1.073V   -59.73mA   -47.23mA   -95.54mA
-1.036V   -42.01mA   -35.32mA   -66.57mA
-963.6mV  -21.55mA   -19.93mA   -32.55mA
-927.3mV  -15.28mA   -14.68mA   -21.5mA
-890.9mV  -11.53mA   -11.44mA   -14.72mA
-818.2mV  -6.261mA   -6.516mA   -6.7mA
-709.1mV  -3.317mA   -2.945mA   -3.729mA
-418.2mV  -133.1uA   -214.2uA   -64.17uA
1.764V    130.9nA    589.6nA    130.8nA
[Ramp]
dV/dt_f  0.5550065/1.775168n   0.3869261/3.184789n   0.6941227/1.100993n
dV/dt_r  0.5352009/1.497042n   0.3619876/2.539088n   0.6835905/0.9784663n
R_load = 50
[Rising Waveform]
R_fixture = 50
V_fixture = 1.8
V_fixture_min = 1.62
V_fixture_max = 1.98
0s        876.6mV    952.2mV    825mV
808.1ps   882.6mV    952.8mV    897.9mV
969.7ps   1V         957.5mV    1.714V
1.051ns   1.229V     969.1mV    1.916V
1.131ns   1.477V     989mV      1.965V
1.212ns   1.651V     1.027V     1.976V
1.374ns   1.784V     1.2V       1.979V
1.616ns   1.798V     1.485V     1.979V
1.939ns   1.799V     1.611V     1.979V
8ns       1.8V       1.62V      1.98V
[Rising Waveform]
R_fixture = 50
V_fixture = 0
V_fixture_min = 0
V_fixture_max = 0
0s        525.9nV    471.5nV    623.8nV
1.051ns   -3.144mV   -1.815mV   3.498mV
1.778ns   89.78mV    -1.861mV   363.6mV
2.02ns    137.2mV    267.7uV    622.8mV
2.586ns   261.3mV    28.32mV    1.035V
2.828ns   376.9mV    43.52mV    1.104V
4.202ns   851.5mV    125.1mV    1.134V
6.141ns   888.1mV    358.3mV    1.135V
7.03ns    888.6mV    545.5mV    1.135V
8ns       888.7mV    601mV      1.135V
[Falling Waveform]
R_fixture = 50
V_fixture = 1.8
V_fixture_min = 1.62
V_fixture_max = 1.98
0s        1.8V       1.62V      1.98V
1.212ns   1.802V     1.621V     1.971V
1.535ns   1.795V     1.621V     1.773V
2.101ns   1.643V     1.621V     1.535V
2.667ns   1.517V     1.583V     1.064V
3.313ns   1.274V     1.522V     855.2mV
3.798ns   1.102V     1.476V     831.7mV
4.687ns   912.1mV    1.401V     826mV
6.061ns   879.6mV    1.176V     825mV
8ns       876.8mV    976.7mV    825mV
[Falling Waveform]
R_fixture = 50
V_fixture = 0
V_fixture_min = 0
V_fixture_max = 0
0s        888.7mV    620.2mV    1.135V
646.5ps   888.6mV    620.2mV    1.135V
808.1ps   871.1mV    620.1mV    1.062V
969.7ps   781.4mV    609.8mV    794.5mV
1.293ns   328.6mV    481.3mV    142.1mV
1.374ns   238.1mV    421.6mV    29.04mV
1.455ns   171mV      358.1mV    3.76mV
1.697ns   18.41mV    191.6mV    554uV
2.343ns   320.2uV    9.435mV    734.5uV
8ns       8.663uV    314.1uV    721.2nV
